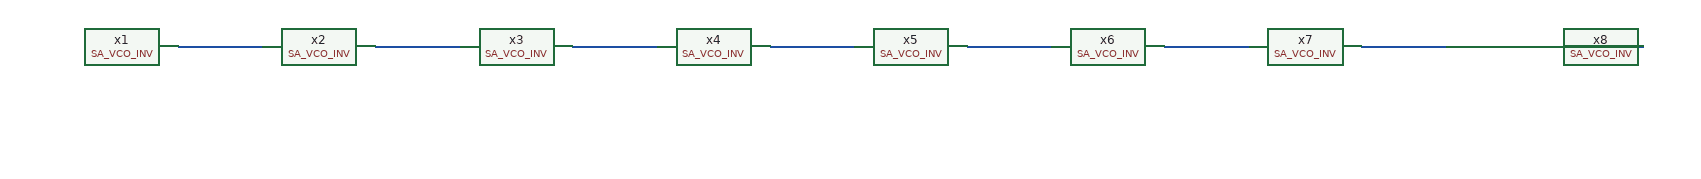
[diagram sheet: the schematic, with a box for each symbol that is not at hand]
v {xschem version=3.4.6RC file_version=1.2
}
G {}
K {}
V {}
S {}
E {}
N 110 -70 200 -70 {lab=#net1}
N 320 -70 410 -70 {lab=#net1}
N 530 -70 620 -70 {lab=#net1}
N 740 -70 830 -70 {lab=#net1}
N 950 -70 1040 -70 {lab=#net1}
N 1160 -70 1250 -70 {lab=#net1}
N 1370 -70 1460 -70 {lab=#net1}
N 1580 -70 1670 -70 {lab=#net1}
C {VCO/SA_VCO_INV.sym} 10 0 0 0 {name=x1}
C {VCO/SA_VCO_INV.sym} 220 0 0 0 {name=x2}
C {VCO/SA_VCO_INV.sym} 430 0 0 0 {name=x3}
C {VCO/SA_VCO_INV.sym} 640 0 0 0 {name=x4}
C {VCO/SA_VCO_INV.sym} 850 0 0 0 {name=x5}
C {VCO/SA_VCO_INV.sym} 1060 0 0 0 {name=x6}
C {VCO/SA_VCO_INV.sym} 1270 0 0 0 {name=x7}
C {VCO/SA_VCO_INV.sym} 1480 0 0 0 {name=x8}
